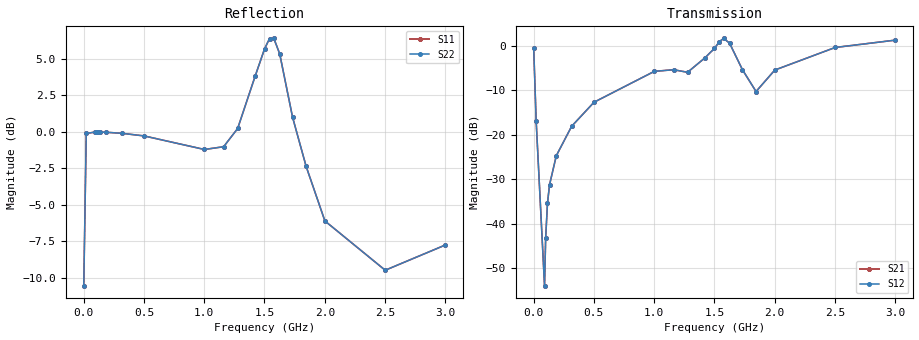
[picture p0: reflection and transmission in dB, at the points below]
!s-Parameter Generated by FASTRON Sdn. Bhd.
!FASTRON P/N : MICC-4R9X
!Keysight Technologies,E4991B,MY54100416,A.01.15
!Date: Fri Aug 28 10:31:00 2026
!Version  : Rev00 Fri Aug 28 10:31:00 2026
!Data & Calibration Information:
!PortZ  Port1:50+j0  Port2:50+j0
!When reading, reference impedance value at option line is always used.
!Remarks : This data is being provided solely for informational purposes.
!Freq	S11	S21	S12	S22
# Hz S dB R 50
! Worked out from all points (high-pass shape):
!   1601 points, 1 MHz to 3 GHz, reference 50 ohm
!   highest |S21| = 1.63 dB at 1.577 GHz (marker M1); lowest = -53.9 dB at 90.97 MHz (marker M2)
!   |S21| within 3 dB of the highest: 1.482 GHz to 1.662 GHz (180.2 MHz wide, 11.5 % of centre); 2.336 GHz to end of sweep (the widest 2 of 3)
!   lowest |S11| = -10.5 dB at 1 MHz (marker M3), VSWR 1.84, Z = 50.8 + j31.3 ohm
!   |S11| at or under -10 dB: start of sweep to 1.147 MHz
!   |S22| runs from -10.5 to 6.5 dB; largest |S21 - S12| = 0
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1000000  -10.55 71.3  -0.47 -17.3  -0.47 -17.3  -10.55 71.3
2.161812e7  -0.11 8.1  -16.99 -80.8  -16.99 -80.8  -0.11 8.1
9.097e7  -0.02 0.0  -53.94 -11.5  -53.94 -11.5  -0.02 0.0
1.003419e8  -0.02 -0.4  -43.20 72.7  -43.20 72.7  -0.02 -0.4
1.153369e8  -0.02 -1.0  -35.47 82.2  -35.47 82.2  -0.02 -1.0
1.322062e8  -0.02 -1.6  -31.30 84.2  -31.30 84.2  -0.02 -1.6
1.884375e8  -0.03 -3.3  -24.75 84.6  -24.75 84.6  -0.03 -3.3
3.15895e8  -0.10 -7.1  -18.12 81.4  -18.12 81.4  -0.10 -7.1
5.014581e8  -0.28 -13.4  -12.72 75.5  -12.72 75.5  -0.28 -13.4
1.001916e9  -1.21 -30.9  -5.78 60.4  -5.78 60.4  -1.21 -30.9
1.161238e9  -1.02 -32.3  -5.42 62.4  -5.42 62.4  -1.02 -32.3
1.277449e9  0.23 -28.6  -5.99 78.6  -5.99 78.6  0.23 -28.6
1.421776e9  3.80 -22.2  -2.74 126.6  -2.74 126.6  3.80 -22.2
1.5005e9  5.69 -4.6  -0.62 170.5  -0.62 170.5  5.69 -4.6
1.541736e9  6.39 9.3  0.92 -162.4  0.92 -162.4  6.39 9.3
1.577349e9  6.41 20.4  1.63 -142.8  1.63 -142.8  6.41 20.4
1.626083e9  5.35 27.0  0.53 -127.7  0.53 -127.7  5.35 27.0
1.732922e9  1.00 28.4  -5.44 -88.6  -5.44 -88.6  1.00 28.4
1.845385e9  -2.37 12.5  -10.31 -32.6  -10.31 -32.6  -2.37 12.5
2.000958e9  -6.11 -13.5  -5.49 12.6  -5.49 12.6  -6.11 -13.5
2.501416e9  -9.49 -72.2  -0.42 19.6  -0.42 19.6  -9.49 -72.2
3e9  -7.76 -101.2  1.23 20.4  1.23 20.4  -7.76 -101.2
